VERSION 5.7 ;
  NOWIREEXTENSIONATPIN ON ;
  DIVIDERCHAR "/" ;
  BUSBITCHARS "[]" ;
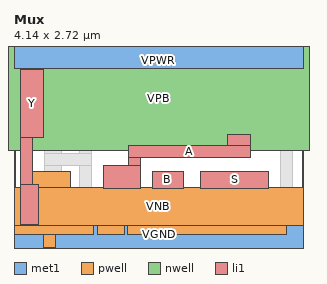
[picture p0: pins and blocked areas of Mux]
MACRO Mux
  CLASS CORE ;
  FOREIGN Mux ;
  ORIGIN 0.000 0.000 ;
  SIZE 4.140 BY 2.720 ;
  PIN VGND
    DIRECTION INOUT ;
    USE GROUND ;
    SHAPE ABUTMENT ;
    PORT
      LAYER met1 ;
        RECT 0.000 -0.240 4.140 0.240 ;
    END
  END VGND
  PIN VNB
    DIRECTION INOUT ;
    USE GROUND ;
    PORT
      LAYER pwell ;
        RECT 0.135 0.785 0.815 1.015 ;
        RECT 0.005 0.235 4.140 0.785 ;
        RECT 0.005 0.105 1.145 0.235 ;
        RECT 1.195 0.105 1.575 0.235 ;
        RECT 1.625 0.105 3.905 0.235 ;
        RECT 0.420 -0.085 0.590 0.105 ;
    END
  END VNB
  PIN VPB
    DIRECTION INOUT ;
    USE POWER ;
    PORT
      LAYER nwell ;
        RECT -0.190 1.305 4.330 2.910 ;
    END
  END VPB
  PIN VPWR
    DIRECTION INOUT ;
    USE POWER ;
    SHAPE ABUTMENT ;
    PORT
      LAYER met1 ;
        RECT 0.000 2.480 4.140 2.960 ;
    END
  END VPWR
  PIN Y
    DIRECTION OUTPUT ;
    USE SIGNAL ;
    ANTENNADIFFAREA 0.429000 ;
    PORT
      LAYER li1 ;
        RECT 0.090 1.495 0.425 2.465 ;
        RECT 0.090 0.825 0.260 1.495 ;
        RECT 0.090 0.255 0.345 0.825 ;
    END
  END Y
  PIN A
    DIRECTION INPUT ;
    USE SIGNAL ;
    ANTENNAGATEAREA 0.126000 ;
    PORT
      LAYER li1 ;
        RECT 3.055 1.380 3.385 1.540 ;
        RECT 1.645 1.210 3.385 1.380 ;
        RECT 1.645 1.095 1.815 1.210 ;
        RECT 1.280 0.765 1.815 1.095 ;
    END
  END A
  PIN B
    DIRECTION INPUT ;
    USE SIGNAL ;
    ANTENNAGATEAREA 0.126000 ;
    PORT
      LAYER li1 ;
        RECT 1.985 0.765 2.420 1.015 ;
    END
  END B
  PIN S
    DIRECTION INPUT ;
    USE SIGNAL ;
    ANTENNAGATEAREA 0.252000 ;
    PORT
      LAYER li1 ;
        RECT 2.670 0.765 3.650 1.015 ;
    END
  END S
  OBS
      LAYER li1 ;
        RECT 0.940 2.330 2.580 2.335 ;
        RECT 0.940 2.165 2.610 2.330 ;
        RECT 0.430 1.260 0.685 1.325 ;
        RECT 0.940 1.260 1.110 2.165 ;
        RECT 2.280 2.070 2.610 2.165 ;
        RECT 3.795 1.900 4.050 2.180 ;
        RECT 1.425 1.850 4.050 1.900 ;
        RECT 1.425 1.730 3.990 1.850 ;
        RECT 1.425 1.555 1.755 1.730 ;
        RECT 0.430 1.090 1.110 1.260 ;
        RECT 0.430 0.995 0.685 1.090 ;
        RECT 0.940 0.470 1.110 1.090 ;
        RECT 3.820 0.670 3.990 1.730 ;
        RECT 1.860 0.470 2.190 0.585 ;
        RECT 0.940 0.300 2.190 0.470 ;
        RECT 3.795 0.340 4.050 0.670 ;
  END
END Mux
END LIBRARY

